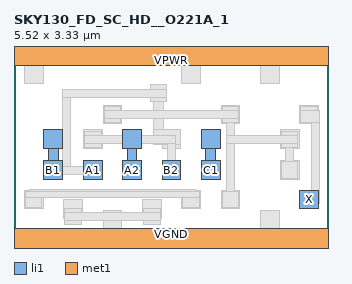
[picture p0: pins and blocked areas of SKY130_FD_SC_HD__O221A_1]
MACRO SKY130_FD_SC_HD__O221A_1
 CLASS CORE ;
 FOREIGN SKY130_FD_SC_HD__O221A_1 0 0 ;
 SIZE 5.5200000000000005 BY 3.33 ;
 ORIGIN 0 0 ;
 SYMMETRY X Y R90 ;
 SITE unit ;
  PIN VPWR
   DIRECTION INOUT ;
   USE POWER ;
   SHAPE ABUTMENT ;
    PORT
     CLASS CORE ;
       LAYER li1 ;
        RECT 0.00000000 3.09000000 5.52000000 3.57000000 ;
       LAYER met1 ;
        RECT 0.00000000 3.09000000 5.52000000 3.57000000 ;
    END
  END VPWR

  PIN VGND
   DIRECTION INOUT ;
   USE POWER ;
   SHAPE ABUTMENT ;
    PORT
     CLASS CORE ;
       LAYER li1 ;
        RECT 0.00000000 -0.24000000 5.52000000 0.24000000 ;
       LAYER met1 ;
        RECT 0.00000000 -0.24000000 5.52000000 0.24000000 ;
    END
  END VGND

  PIN X
   DIRECTION INOUT ;
   USE SIGNAL ;
   SHAPE ABUTMENT ;
    PORT
     CLASS CORE ;
       LAYER li1 ;
        RECT 5.01000000 0.58000000 5.34000000 0.91000000 ;
    END
  END X

  PIN C1
   DIRECTION INOUT ;
   USE SIGNAL ;
   SHAPE ABUTMENT ;
    PORT
     CLASS CORE ;
       LAYER li1 ;
        RECT 3.28500000 1.09500000 3.61500000 1.42500000 ;
        RECT 3.36500000 1.42500000 3.53500000 1.63500000 ;
        RECT 3.28500000 1.63500000 3.61500000 1.96500000 ;
    END
  END C1

  PIN A1
   DIRECTION INOUT ;
   USE SIGNAL ;
   SHAPE ABUTMENT ;
    PORT
     CLASS CORE ;
       LAYER li1 ;
        RECT 1.21500000 1.09500000 1.54500000 1.42500000 ;
    END
  END A1

  PIN A2
   DIRECTION INOUT ;
   USE SIGNAL ;
   SHAPE ABUTMENT ;
    PORT
     CLASS CORE ;
       LAYER li1 ;
        RECT 1.90500000 1.09500000 2.23500000 1.42500000 ;
        RECT 1.98500000 1.42500000 2.15500000 1.63500000 ;
        RECT 1.90500000 1.63500000 2.23500000 1.96500000 ;
    END
  END A2

  PIN B2
   DIRECTION INOUT ;
   USE SIGNAL ;
   SHAPE ABUTMENT ;
    PORT
     CLASS CORE ;
       LAYER li1 ;
        RECT 2.59500000 1.09500000 2.92500000 1.42500000 ;
    END
  END B2

  PIN B1
   DIRECTION INOUT ;
   USE SIGNAL ;
   SHAPE ABUTMENT ;
    PORT
     CLASS CORE ;
       LAYER li1 ;
        RECT 0.52500000 1.09500000 0.85500000 1.42500000 ;
        RECT 0.60500000 1.42500000 0.77500000 1.63500000 ;
        RECT 0.52500000 1.63500000 0.85500000 1.96500000 ;
    END
  END B1

 OBS
    LAYER polycont ;
     RECT 0.60500000 1.17500000 0.77500000 1.34500000 ;
     RECT 1.29500000 1.17500000 1.46500000 1.34500000 ;
     RECT 1.98500000 1.17500000 2.15500000 1.34500000 ;
     RECT 2.67500000 1.17500000 2.84500000 1.34500000 ;
     RECT 3.36500000 1.17500000 3.53500000 1.34500000 ;
     RECT 4.74500000 1.17500000 4.91500000 1.34500000 ;
     RECT 0.60500000 1.71500000 0.77500000 1.88500000 ;
     RECT 1.29500000 1.71500000 1.46500000 1.88500000 ;
     RECT 1.98500000 1.71500000 2.15500000 1.88500000 ;
     RECT 2.67500000 1.71500000 2.84500000 1.88500000 ;
     RECT 3.36500000 1.71500000 3.53500000 1.88500000 ;
     RECT 4.74500000 1.71500000 4.91500000 1.88500000 ;

    LAYER pdiffc ;
     RECT 1.64000000 2.15000000 1.81000000 2.32000000 ;
     RECT 3.71000000 2.15000000 3.88000000 2.32000000 ;
     RECT 5.09000000 2.15000000 5.26000000 2.32000000 ;
     RECT 0.26000000 2.86000000 0.43000000 3.03000000 ;
     RECT 3.02000000 2.86000000 3.19000000 3.03000000 ;
     RECT 4.40000000 2.86000000 4.57000000 3.03000000 ;

    LAYER ndiffc ;
     RECT 1.64000000 0.30000000 1.81000000 0.47000000 ;
     RECT 4.40000000 0.30000000 4.57000000 0.47000000 ;
     RECT 0.95000000 0.50000000 1.12000000 0.67000000 ;
     RECT 2.33000000 0.50000000 2.50000000 0.67000000 ;
     RECT 0.26000000 0.66000000 0.43000000 0.83000000 ;
     RECT 3.02000000 0.66000000 3.19000000 0.83000000 ;
     RECT 3.71000000 0.66000000 3.88000000 0.83000000 ;
     RECT 5.09000000 0.66000000 5.26000000 0.83000000 ;

    LAYER li1 ;
     RECT 0.00000000 -0.24000000 5.52000000 0.24000000 ;
     RECT 1.56000000 0.24000000 1.89000000 0.55000000 ;
     RECT 4.32000000 0.24000000 4.65000000 0.55000000 ;
     RECT 0.95000000 0.36500000 1.12000000 0.42000000 ;
     RECT 0.87000000 0.42000000 1.20000000 0.75000000 ;
     RECT 2.33000000 0.36500000 2.50000000 0.42000000 ;
     RECT 2.25000000 0.42000000 2.58000000 0.75000000 ;
     RECT 0.18000000 0.58000000 0.51000000 0.91000000 ;
     RECT 2.94000000 0.58000000 3.27000000 0.91000000 ;
     RECT 3.63000000 0.58000000 3.96000000 0.91000000 ;
     RECT 5.01000000 0.58000000 5.34000000 0.91000000 ;
     RECT 1.21500000 1.09500000 1.54500000 1.42500000 ;
     RECT 2.59500000 1.09500000 2.92500000 1.42500000 ;
     RECT 4.66500000 1.09500000 4.99500000 1.42500000 ;
     RECT 0.52500000 1.09500000 0.85500000 1.42500000 ;
     RECT 0.60500000 1.42500000 0.77500000 1.63500000 ;
     RECT 0.52500000 1.63500000 0.85500000 1.96500000 ;
     RECT 1.21500000 1.63500000 1.54500000 1.96500000 ;
     RECT 1.90500000 1.09500000 2.23500000 1.42500000 ;
     RECT 1.98500000 1.42500000 2.15500000 1.63500000 ;
     RECT 1.90500000 1.63500000 2.23500000 1.96500000 ;
     RECT 3.28500000 1.09500000 3.61500000 1.42500000 ;
     RECT 3.36500000 1.42500000 3.53500000 1.63500000 ;
     RECT 3.28500000 1.63500000 3.61500000 1.96500000 ;
     RECT 4.66500000 1.63500000 4.99500000 1.96500000 ;
     RECT 1.56000000 2.07000000 1.89000000 2.40000000 ;
     RECT 3.63000000 2.07000000 3.96000000 2.40000000 ;
     RECT 5.01000000 2.07000000 5.34000000 2.40000000 ;
     RECT 2.59500000 1.63500000 2.92500000 1.71500000 ;
     RECT 2.44500000 1.71500000 2.92500000 1.96500000 ;
     RECT 2.44500000 1.96500000 2.61500000 2.69500000 ;
     RECT 0.18000000 2.78000000 0.51000000 3.09000000 ;
     RECT 2.94000000 2.78000000 3.27000000 3.09000000 ;
     RECT 4.32000000 2.78000000 4.65000000 3.09000000 ;
     RECT 0.00000000 3.09000000 5.52000000 3.57000000 ;

    LAYER viali ;
     RECT 1.64000000 -0.08500000 1.81000000 0.08500000 ;
     RECT 0.95000000 0.36500000 1.12000000 0.53500000 ;
     RECT 2.33000000 0.36500000 2.50000000 0.53500000 ;
     RECT 0.26000000 0.66000000 0.43000000 0.83000000 ;
     RECT 3.02000000 0.66000000 3.19000000 0.83000000 ;
     RECT 3.71000000 0.66000000 3.88000000 0.83000000 ;
     RECT 5.09000000 0.66000000 5.26000000 0.83000000 ;
     RECT 1.29500000 1.17500000 1.46500000 1.34500000 ;
     RECT 2.67500000 1.17500000 2.84500000 1.34500000 ;
     RECT 4.74500000 1.17500000 4.91500000 1.34500000 ;
     RECT 1.29500000 1.71500000 1.46500000 1.88500000 ;
     RECT 4.74500000 1.71500000 4.91500000 1.88500000 ;
     RECT 1.64000000 2.15000000 1.81000000 2.32000000 ;
     RECT 3.71000000 2.15000000 3.88000000 2.32000000 ;
     RECT 5.09000000 2.15000000 5.26000000 2.32000000 ;
     RECT 2.44500000 2.52500000 2.61500000 2.69500000 ;
     RECT 3.02000000 3.24500000 3.19000000 3.41500000 ;

    LAYER met1 ;
     RECT 0.00000000 -0.24000000 5.52000000 0.24000000 ;
     RECT 0.89000000 0.30500000 1.18000000 0.38000000 ;
     RECT 2.27000000 0.30500000 2.56000000 0.38000000 ;
     RECT 0.89000000 0.38000000 2.56000000 0.52000000 ;
     RECT 0.89000000 0.52000000 1.18000000 0.59500000 ;
     RECT 2.27000000 0.52000000 2.56000000 0.59500000 ;
     RECT 0.20000000 0.60000000 0.49000000 0.78500000 ;
     RECT 2.96000000 0.60000000 3.25000000 0.78500000 ;
     RECT 0.20000000 0.78500000 3.25000000 0.89000000 ;
     RECT 0.27500000 0.89000000 3.17500000 0.92500000 ;
     RECT 2.61500000 1.11500000 2.90500000 1.40500000 ;
     RECT 1.23500000 1.65500000 1.52500000 1.73000000 ;
     RECT 2.69000000 1.40500000 2.83000000 1.73000000 ;
     RECT 1.23500000 1.73000000 2.83000000 1.87000000 ;
     RECT 1.23500000 1.87000000 1.52500000 1.94500000 ;
     RECT 3.65000000 0.60000000 3.94000000 0.89000000 ;
     RECT 4.68500000 1.11500000 4.97500000 1.40500000 ;
     RECT 4.76000000 1.40500000 4.90000000 1.65500000 ;
     RECT 3.72500000 0.89000000 3.86500000 1.73000000 ;
     RECT 4.68500000 1.65500000 4.97500000 1.73000000 ;
     RECT 3.72500000 1.73000000 4.97500000 1.87000000 ;
     RECT 4.68500000 1.87000000 4.97500000 1.94500000 ;
     RECT 3.72500000 1.87000000 3.86500000 2.09000000 ;
     RECT 1.58000000 2.09000000 1.87000000 2.16500000 ;
     RECT 3.65000000 2.09000000 3.94000000 2.16500000 ;
     RECT 1.58000000 2.16500000 3.94000000 2.30500000 ;
     RECT 1.58000000 2.30500000 1.87000000 2.38000000 ;
     RECT 3.65000000 2.30500000 3.94000000 2.38000000 ;
     RECT 5.03000000 0.60000000 5.32000000 0.67500000 ;
     RECT 5.03000000 0.67500000 5.36000000 0.89000000 ;
     RECT 5.22000000 0.89000000 5.36000000 2.09000000 ;
     RECT 5.03000000 2.09000000 5.36000000 2.30500000 ;
     RECT 5.03000000 2.30500000 5.32000000 2.38000000 ;
     RECT 1.23500000 1.11500000 1.52500000 1.19000000 ;
     RECT 0.85000000 1.19000000 1.52500000 1.33000000 ;
     RECT 1.23500000 1.33000000 1.52500000 1.40500000 ;
     RECT 0.85000000 1.33000000 0.99000000 2.54000000 ;
     RECT 2.38500000 2.46500000 2.67500000 2.54000000 ;
     RECT 0.85000000 2.54000000 2.67500000 2.68000000 ;
     RECT 2.38500000 2.68000000 2.67500000 2.75500000 ;
     RECT 0.00000000 3.09000000 5.52000000 3.57000000 ;

    LAYER via ;


    LAYER met2 ;


    LAYER via2 ;


    LAYER met3 ;


 END
END SKY130_FD_SC_HD__O221A_1
